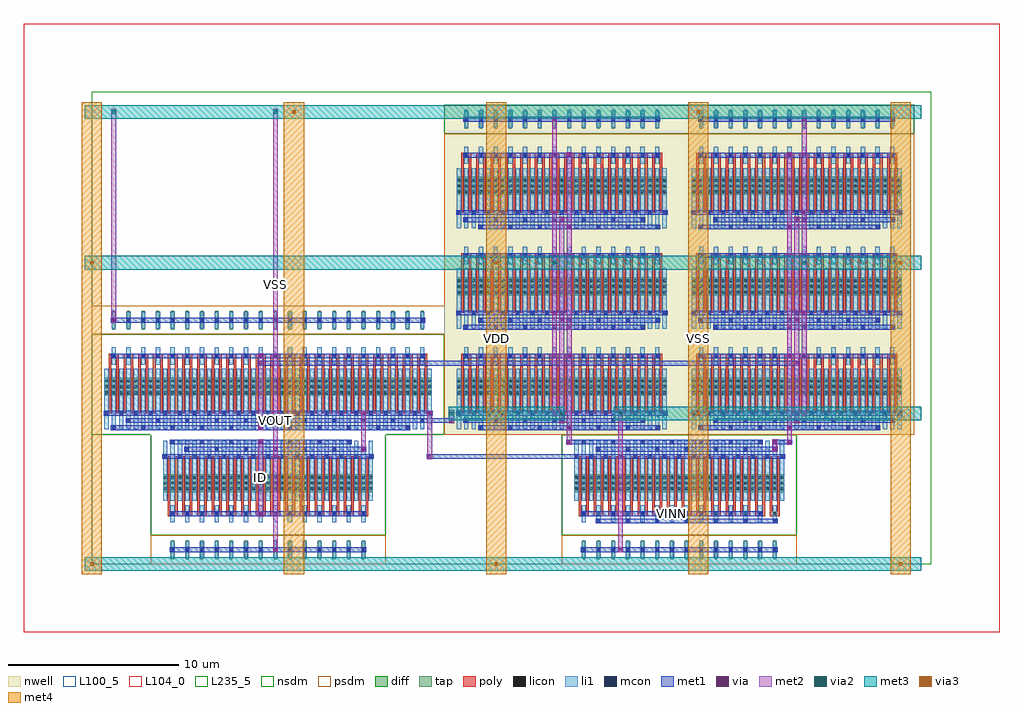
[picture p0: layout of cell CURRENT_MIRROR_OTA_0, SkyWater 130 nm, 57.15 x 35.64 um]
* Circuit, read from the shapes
.subckt CURRENT_MIRROR_OTA_0 ID VDD VINN VINP VOUT VSS
XM1 n1 n1 n2 VSS sky130_fd_pr__nfet_01v8 w=1.05 l=0.15 m=22
XM2 VOUT n1 n2 VSS sky130_fd_pr__nfet_01v8 w=1.05 l=0.15 m=22
XM3 ID ID VSS VSS sky130_fd_pr__nfet_01v8 w=1.05 l=0.15 m=14
XM4 n2 ID VSS VSS sky130_fd_pr__nfet_01v8 w=1.05 l=0.15 m=14
XM5 n3 VINN n2 VSS sky130_fd_pr__nfet_01v8 w=1.05 l=0.15 m=14
XM6 n4 VINP n2 VSS sky130_fd_pr__nfet_01v8 w=1.05 l=0.15 m=14
XM7 VOUT n3 VDD VDD sky130_fd_pr__pfet_01v8 w=1.05 l=0.15 m=42
XM8 n3 n3 VDD VDD sky130_fd_pr__pfet_01v8 w=1.05 l=0.15 m=42
XM9 n4 n4 VDD VDD sky130_fd_pr__pfet_01v8 w=1.05 l=0.15 m=42
XM10 n1 n4 VDD VDD sky130_fd_pr__pfet_01v8 w=1.05 l=0.15 m=42
.ends

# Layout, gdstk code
from math import pi, radians
import gdstk
lib = gdstk.Library(unit=1e-6, precision=1e-09)
def R(c, l, rs):  # rectangles x0, y0, x1, y1
    for r in rs: c.add(gdstk.rectangle(r[:2], r[2:], *l))
def A(c, l, x, y, w, h, nx, ny, dx, dy):  # array of equal rectangles
    R(c, l, [(x+i*dx, y+j*dy, x+i*dx+w, y+j*dy+h) for i in range(nx) for j in range(ny)])
def P(c, l, *ps):  # polygons
    for p in ps: c.add(gdstk.Polygon(p, *l))
nwell = (64, 20)
diff = (65, 20)
tap = (65, 44)
poly = (66, 20)
licon = (66, 44)
li1 = (67, 20)
mcon = (67, 44)
met1 = (68, 20)
via = (68, 44)
met2 = (69, 20)
via2 = (69, 44)
met3 = (70, 20)
via3 = (70, 44)
met4 = (71, 20)
nsdm = (93, 44)
psdm = (94, 20)
L100_5 = (100, 5)
L104_0 = (104, 0)
L235_5 = (235, 5)

scm_nmos_76211906_x7_y1_ = lib.new_cell('SCM_NMOS_76211906_X7_Y1_1725195708')
R(scm_nmos_76211906_x7_y1_, diff, [(0.735,2.31,13.025,3.36)])
A(scm_nmos_76211906_x7_y1_, tap, 1.205, 6.16, 0.17, 1.12, 14, 1, 0.86, 0)
A(scm_nmos_76211906_x7_y1_, poly, 1, 1.26, 0.15, 3.36, 28, 1, 0.43, 0)
A(scm_nmos_76211906_x7_y1_, poly, 1, 4.485, 0.58, 0.27, 14, 1, 0.86, 0)
A(scm_nmos_76211906_x7_y1_, licon, 0.775, 2.39, 0.17, 0.17, 3, 3, 0.43, 0.34)
A(scm_nmos_76211906_x7_y1_, licon, 1.635, 2.39, 0.17, 0.17, 3, 3, 0.43, 0.34)
A(scm_nmos_76211906_x7_y1_, licon, 2.495, 2.39, 0.17, 0.17, 3, 3, 0.43, 0.34)
A(scm_nmos_76211906_x7_y1_, licon, 3.355, 2.39, 0.17, 0.17, 3, 3, 0.43, 0.34)
A(scm_nmos_76211906_x7_y1_, licon, 4.215, 2.39, 0.17, 0.17, 3, 3, 0.43, 0.34)
A(scm_nmos_76211906_x7_y1_, licon, 5.075, 2.39, 0.17, 0.17, 3, 3, 0.43, 0.34)
A(scm_nmos_76211906_x7_y1_, licon, 5.935, 2.39, 0.17, 0.17, 3, 3, 0.43, 0.34)
A(scm_nmos_76211906_x7_y1_, licon, 6.795, 2.39, 0.17, 0.17, 3, 3, 0.43, 0.34)
A(scm_nmos_76211906_x7_y1_, licon, 7.655, 2.39, 0.17, 0.17, 3, 3, 0.43, 0.34)
A(scm_nmos_76211906_x7_y1_, licon, 8.515, 2.39, 0.17, 0.17, 3, 3, 0.43, 0.34)
A(scm_nmos_76211906_x7_y1_, licon, 9.375, 2.39, 0.17, 0.17, 3, 3, 0.43, 0.34)
A(scm_nmos_76211906_x7_y1_, licon, 10.235, 2.39, 0.17, 0.17, 3, 3, 0.43, 0.34)
A(scm_nmos_76211906_x7_y1_, licon, 11.095, 2.39, 0.17, 0.17, 3, 3, 0.43, 0.34)
A(scm_nmos_76211906_x7_y1_, licon, 11.955, 2.39, 0.17, 0.17, 3, 3, 0.43, 0.34)
A(scm_nmos_76211906_x7_y1_, licon, 1.205, 4.535, 0.17, 0.17, 14, 2, 0.86, 2.1)
A(scm_nmos_76211906_x7_y1_, li1, 0.735, 0.335, 0.25, 3.53, 29, 1, 0.43, 0)
A(scm_nmos_76211906_x7_y1_, li1, 1.165, 4.115, 0.25, 1.01, 14, 2, 0.86, 2.1)
A(scm_nmos_76211906_x7_y1_, mcon, 1.205, 0.335, 0.17, 0.17, 7, 1, 1.72, 0)
A(scm_nmos_76211906_x7_y1_, mcon, 2.065, 0.755, 0.17, 0.17, 7, 1, 1.72, 0)
A(scm_nmos_76211906_x7_y1_, mcon, 0.775, 1.175, 0.17, 0.17, 15, 1, 0.86, 0)
A(scm_nmos_76211906_x7_y1_, mcon, 1.205, 4.535, 0.17, 0.17, 14, 2, 0.86, 2.1)
R(scm_nmos_76211906_x7_y1_, met1, [(1.12,0.28,11.78,0.56), (1.98,0.7,12.64,0.98), (0.69,1.12,13.07,1.4), (1.12,4.48,12.64,4.76), (1.12,6.58,12.64,6.86)])
R(scm_nmos_76211906_x7_y1_, via, [(6.375,0.345,6.525,0.495), (7.235,1.185,7.385,1.335), (6.375,4.545,6.525,4.695), (7.235,6.645,7.385,6.795)])
R(scm_nmos_76211906_x7_y1_, met2, [(6.31,0.26,6.59,4.78), (7.17,1.1,7.45,6.88)])
R(scm_nmos_76211906_x7_y1_, nsdm, [(0,0,13.76,5.88)])
R(scm_nmos_76211906_x7_y1_, psdm, [(0,5.88,13.76,7.56)])
R(scm_nmos_76211906_x7_y1_, L100_5, [(0,0,13.76,7.56)])

scm_pmos_77874900_x7_y3_ = lib.new_cell('SCM_PMOS_77874900_X7_Y3_1725195710')
R(scm_pmos_77874900_x7_y3_, nwell, [(0,0,13.76,19.32)])
A(scm_pmos_77874900_x7_y3_, diff, 0.735, 2.31, 12.29, 1.05, 1, 3, 0, 5.88)
A(scm_pmos_77874900_x7_y3_, tap, 1.205, 17.92, 0.17, 1.12, 14, 1, 0.86, 0)
A(scm_pmos_77874900_x7_y3_, poly, 1, 1.26, 0.15, 3.36, 28, 3, 0.43, 5.88)
A(scm_pmos_77874900_x7_y3_, poly, 1, 4.485, 0.58, 0.27, 14, 3, 0.86, 5.88)
A(scm_pmos_77874900_x7_y3_, licon, 0.775, 2.39, 0.17, 0.17, 3, 3, 0.43, 0.34)
A(scm_pmos_77874900_x7_y3_, licon, 1.635, 2.39, 0.17, 0.17, 3, 3, 0.43, 0.34)
A(scm_pmos_77874900_x7_y3_, licon, 2.495, 2.39, 0.17, 0.17, 3, 3, 0.43, 0.34)
A(scm_pmos_77874900_x7_y3_, licon, 3.355, 2.39, 0.17, 0.17, 3, 3, 0.43, 0.34)
A(scm_pmos_77874900_x7_y3_, licon, 4.215, 2.39, 0.17, 0.17, 3, 3, 0.43, 0.34)
A(scm_pmos_77874900_x7_y3_, licon, 5.075, 2.39, 0.17, 0.17, 3, 3, 0.43, 0.34)
A(scm_pmos_77874900_x7_y3_, licon, 5.935, 2.39, 0.17, 0.17, 3, 3, 0.43, 0.34)
A(scm_pmos_77874900_x7_y3_, licon, 6.795, 2.39, 0.17, 0.17, 3, 3, 0.43, 0.34)
A(scm_pmos_77874900_x7_y3_, licon, 7.655, 2.39, 0.17, 0.17, 3, 3, 0.43, 0.34)
A(scm_pmos_77874900_x7_y3_, licon, 8.515, 2.39, 0.17, 0.17, 3, 3, 0.43, 0.34)
A(scm_pmos_77874900_x7_y3_, licon, 9.375, 2.39, 0.17, 0.17, 3, 3, 0.43, 0.34)
A(scm_pmos_77874900_x7_y3_, licon, 10.235, 2.39, 0.17, 0.17, 3, 3, 0.43, 0.34)
A(scm_pmos_77874900_x7_y3_, licon, 11.095, 2.39, 0.17, 0.17, 3, 3, 0.43, 0.34)
A(scm_pmos_77874900_x7_y3_, licon, 11.955, 2.39, 0.17, 0.17, 3, 3, 0.43, 0.34)
A(scm_pmos_77874900_x7_y3_, licon, 1.205, 4.535, 0.17, 0.17, 14, 3, 0.86, 5.88)
A(scm_pmos_77874900_x7_y3_, licon, 0.775, 8.27, 0.17, 0.17, 3, 3, 0.43, 0.34)
A(scm_pmos_77874900_x7_y3_, licon, 1.635, 8.27, 0.17, 0.17, 3, 3, 0.43, 0.34)
A(scm_pmos_77874900_x7_y3_, licon, 2.495, 8.27, 0.17, 0.17, 3, 3, 0.43, 0.34)
A(scm_pmos_77874900_x7_y3_, licon, 3.355, 8.27, 0.17, 0.17, 3, 3, 0.43, 0.34)
A(scm_pmos_77874900_x7_y3_, licon, 4.215, 8.27, 0.17, 0.17, 3, 3, 0.43, 0.34)
A(scm_pmos_77874900_x7_y3_, licon, 5.075, 8.27, 0.17, 0.17, 3, 3, 0.43, 0.34)
A(scm_pmos_77874900_x7_y3_, licon, 5.935, 8.27, 0.17, 0.17, 3, 3, 0.43, 0.34)
A(scm_pmos_77874900_x7_y3_, licon, 6.795, 8.27, 0.17, 0.17, 3, 3, 0.43, 0.34)
A(scm_pmos_77874900_x7_y3_, licon, 7.655, 8.27, 0.17, 0.17, 3, 3, 0.43, 0.34)
A(scm_pmos_77874900_x7_y3_, licon, 8.515, 8.27, 0.17, 0.17, 3, 3, 0.43, 0.34)
A(scm_pmos_77874900_x7_y3_, licon, 9.375, 8.27, 0.17, 0.17, 3, 3, 0.43, 0.34)
A(scm_pmos_77874900_x7_y3_, licon, 10.235, 8.27, 0.17, 0.17, 3, 3, 0.43, 0.34)
A(scm_pmos_77874900_x7_y3_, licon, 11.095, 8.27, 0.17, 0.17, 3, 3, 0.43, 0.34)
A(scm_pmos_77874900_x7_y3_, licon, 11.955, 8.27, 0.17, 0.17, 3, 3, 0.43, 0.34)
A(scm_pmos_77874900_x7_y3_, licon, 0.775, 14.15, 0.17, 0.17, 3, 3, 0.43, 0.34)
A(scm_pmos_77874900_x7_y3_, licon, 1.635, 14.15, 0.17, 0.17, 3, 3, 0.43, 0.34)
A(scm_pmos_77874900_x7_y3_, licon, 2.495, 14.15, 0.17, 0.17, 3, 3, 0.43, 0.34)
A(scm_pmos_77874900_x7_y3_, licon, 3.355, 14.15, 0.17, 0.17, 3, 3, 0.43, 0.34)
A(scm_pmos_77874900_x7_y3_, licon, 4.215, 14.15, 0.17, 0.17, 3, 3, 0.43, 0.34)
A(scm_pmos_77874900_x7_y3_, licon, 5.075, 14.15, 0.17, 0.17, 3, 3, 0.43, 0.34)
A(scm_pmos_77874900_x7_y3_, licon, 5.935, 14.15, 0.17, 0.17, 3, 3, 0.43, 0.34)
A(scm_pmos_77874900_x7_y3_, licon, 6.795, 14.15, 0.17, 0.17, 3, 3, 0.43, 0.34)
A(scm_pmos_77874900_x7_y3_, licon, 7.655, 14.15, 0.17, 0.17, 3, 3, 0.43, 0.34)
A(scm_pmos_77874900_x7_y3_, licon, 8.515, 14.15, 0.17, 0.17, 3, 3, 0.43, 0.34)
A(scm_pmos_77874900_x7_y3_, licon, 9.375, 14.15, 0.17, 0.17, 3, 3, 0.43, 0.34)
A(scm_pmos_77874900_x7_y3_, licon, 10.235, 14.15, 0.17, 0.17, 3, 3, 0.43, 0.34)
A(scm_pmos_77874900_x7_y3_, licon, 11.095, 14.15, 0.17, 0.17, 3, 3, 0.43, 0.34)
A(scm_pmos_77874900_x7_y3_, licon, 11.955, 14.15, 0.17, 0.17, 3, 3, 0.43, 0.34)
R(scm_pmos_77874900_x7_y3_, licon, [(1.205,18.395,1.375,18.565), (1.205,18.395,1.375,18.565), (1.205,18.395,1.375,18.565), (2.065,18.395,2.235,18.565), (2.065,18.395,2.235,18.565), (2.065,18.395,2.235,18.565), (2.925,18.395,3.095,18.565), (2.925,18.395,3.095,18.565), (2.925,18.395,3.095,18.565), (3.785,18.395,3.955,18.565), (3.785,18.395,3.955,18.565), (3.785,18.395,3.955,18.565), (4.645,18.395,4.815,18.565), (4.645,18.395,4.815,18.565), (4.645,18.395,4.815,18.565), (5.505,18.395,5.675,18.565), (5.505,18.395,5.675,18.565), (5.505,18.395,5.675,18.565), (6.365,18.395,6.535,18.565), (6.365,18.395,6.535,18.565), (6.365,18.395,6.535,18.565), (7.225,18.395,7.395,18.565), (7.225,18.395,7.395,18.565), (7.225,18.395,7.395,18.565), (8.085,18.395,8.255,18.565), (8.085,18.395,8.255,18.565), (8.085,18.395,8.255,18.565), (8.945,18.395,9.115,18.565), (8.945,18.395,9.115,18.565), (8.945,18.395,9.115,18.565), (9.805,18.395,9.975,18.565), (9.805,18.395,9.975,18.565), (9.805,18.395,9.975,18.565), (10.665,18.395,10.835,18.565), (10.665,18.395,10.835,18.565), (10.665,18.395,10.835,18.565), (11.525,18.395,11.695,18.565), (11.525,18.395,11.695,18.565), (11.525,18.395,11.695,18.565), (12.385,18.395,12.555,18.565), (12.385,18.395,12.555,18.565), (12.385,18.395,12.555,18.565)])
A(scm_pmos_77874900_x7_y3_, li1, 0.735, 0.335, 0.25, 3.53, 29, 3, 0.43, 5.88)
A(scm_pmos_77874900_x7_y3_, li1, 1.165, 4.115, 0.25, 1.01, 14, 3, 0.86, 5.88)
A(scm_pmos_77874900_x7_y3_, li1, 1.165, 17.975, 0.25, 1.01, 14, 1, 0.86, 0)
A(scm_pmos_77874900_x7_y3_, mcon, 1.205, 0.335, 0.17, 0.17, 7, 2, 1.72, 6.3)
A(scm_pmos_77874900_x7_y3_, mcon, 2.065, 0.755, 0.17, 0.17, 7, 2, 1.72, 5.46)
A(scm_pmos_77874900_x7_y3_, mcon, 0.775, 1.175, 0.17, 0.17, 15, 3, 0.86, 5.88)
A(scm_pmos_77874900_x7_y3_, mcon, 1.205, 4.535, 0.17, 0.17, 14, 3, 0.86, 5.88)
A(scm_pmos_77874900_x7_y3_, mcon, 1.205, 12.095, 0.17, 0.17, 7, 1, 1.72, 0)
A(scm_pmos_77874900_x7_y3_, mcon, 2.065, 12.515, 0.17, 0.17, 7, 1, 1.72, 0)
A(scm_pmos_77874900_x7_y3_, mcon, 1.205, 18.395, 0.17, 0.17, 14, 1, 0.86, 0)
A(scm_pmos_77874900_x7_y3_, met1, 0.69, 1.12, 12.38, 0.28, 1, 3, 0, 5.88)
A(scm_pmos_77874900_x7_y3_, met1, 1.12, 4.48, 11.52, 0.28, 1, 3, 0, 5.88)
R(scm_pmos_77874900_x7_y3_, met1, [(1.12,0.28,11.78,0.56), (1.98,0.7,12.64,0.98), (1.98,6.16,12.64,6.44), (1.12,6.58,11.78,6.86), (1.12,12.04,11.78,12.32), (1.98,12.46,12.64,12.74), (1.12,18.34,12.64,18.62)])
A(scm_pmos_77874900_x7_y3_, via, 6.805, 0.765, 0.15, 0.15, 1, 3, 0, 5.88)
A(scm_pmos_77874900_x7_y3_, via, 7.235, 1.185, 0.15, 0.15, 1, 3, 0, 5.88)
R(scm_pmos_77874900_x7_y3_, via, [(6.375,0.345,6.525,0.495), (6.375,4.545,6.525,4.695), (6.375,6.225,6.525,6.375), (6.375,10.425,6.525,10.575), (6.375,12.105,6.525,12.255), (6.375,16.305,6.525,16.455), (7.235,18.405,7.385,18.555)])
R(scm_pmos_77874900_x7_y3_, met2, [(6.31,0.26,6.59,16.54), (6.74,0.68,7.02,12.76), (7.17,1.1,7.45,18.64)])
R(scm_pmos_77874900_x7_y3_, nsdm, [(0,17.64,13.76,19.32)])
R(scm_pmos_77874900_x7_y3_, psdm, [(0,0,13.76,17.64)])
R(scm_pmos_77874900_x7_y3_, L100_5, [(0,0,13.76,19.32)])

scm_nmos_b_90984876_x11_ = lib.new_cell('SCM_NMOS_B_90984876_X11_Y1_1725195709')
R(scm_nmos_b_90984876_x11_, diff, [(0.735,2.31,19.905,3.36)])
A(scm_nmos_b_90984876_x11_, tap, 1.205, 6.16, 0.17, 1.12, 22, 1, 0.86, 0)
A(scm_nmos_b_90984876_x11_, poly, 1, 1.26, 0.15, 3.36, 44, 1, 0.43, 0)
A(scm_nmos_b_90984876_x11_, poly, 1, 4.485, 0.58, 0.27, 22, 1, 0.86, 0)
A(scm_nmos_b_90984876_x11_, licon, 0.775, 2.39, 0.17, 0.17, 3, 3, 0.43, 0.34)
A(scm_nmos_b_90984876_x11_, licon, 1.635, 2.39, 0.17, 0.17, 3, 3, 0.43, 0.34)
A(scm_nmos_b_90984876_x11_, licon, 2.495, 2.39, 0.17, 0.17, 3, 3, 0.43, 0.34)
A(scm_nmos_b_90984876_x11_, licon, 3.355, 2.39, 0.17, 0.17, 3, 3, 0.43, 0.34)
A(scm_nmos_b_90984876_x11_, licon, 4.215, 2.39, 0.17, 0.17, 3, 3, 0.43, 0.34)
A(scm_nmos_b_90984876_x11_, licon, 5.075, 2.39, 0.17, 0.17, 3, 3, 0.43, 0.34)
A(scm_nmos_b_90984876_x11_, licon, 5.935, 2.39, 0.17, 0.17, 3, 3, 0.43, 0.34)
A(scm_nmos_b_90984876_x11_, licon, 6.795, 2.39, 0.17, 0.17, 3, 3, 0.43, 0.34)
A(scm_nmos_b_90984876_x11_, licon, 7.655, 2.39, 0.17, 0.17, 3, 3, 0.43, 0.34)
A(scm_nmos_b_90984876_x11_, licon, 8.515, 2.39, 0.17, 0.17, 3, 3, 0.43, 0.34)
A(scm_nmos_b_90984876_x11_, licon, 9.375, 2.39, 0.17, 0.17, 3, 3, 0.43, 0.34)
A(scm_nmos_b_90984876_x11_, licon, 10.235, 2.39, 0.17, 0.17, 3, 3, 0.43, 0.34)
A(scm_nmos_b_90984876_x11_, licon, 11.095, 2.39, 0.17, 0.17, 3, 3, 0.43, 0.34)
A(scm_nmos_b_90984876_x11_, licon, 11.955, 2.39, 0.17, 0.17, 3, 3, 0.43, 0.34)
A(scm_nmos_b_90984876_x11_, licon, 12.815, 2.39, 0.17, 0.17, 3, 3, 0.43, 0.34)
A(scm_nmos_b_90984876_x11_, licon, 13.675, 2.39, 0.17, 0.17, 3, 3, 0.43, 0.34)
A(scm_nmos_b_90984876_x11_, licon, 14.535, 2.39, 0.17, 0.17, 3, 3, 0.43, 0.34)
A(scm_nmos_b_90984876_x11_, licon, 15.395, 2.39, 0.17, 0.17, 3, 3, 0.43, 0.34)
A(scm_nmos_b_90984876_x11_, licon, 16.255, 2.39, 0.17, 0.17, 3, 3, 0.43, 0.34)
A(scm_nmos_b_90984876_x11_, licon, 17.115, 2.39, 0.17, 0.17, 3, 3, 0.43, 0.34)
A(scm_nmos_b_90984876_x11_, licon, 17.975, 2.39, 0.17, 0.17, 3, 3, 0.43, 0.34)
A(scm_nmos_b_90984876_x11_, licon, 18.835, 2.39, 0.17, 0.17, 3, 3, 0.43, 0.34)
A(scm_nmos_b_90984876_x11_, licon, 1.205, 4.535, 0.17, 0.17, 22, 2, 0.86, 2.1)
A(scm_nmos_b_90984876_x11_, li1, 0.735, 0.335, 0.25, 3.53, 45, 1, 0.43, 0)
A(scm_nmos_b_90984876_x11_, li1, 1.165, 4.115, 0.25, 1.01, 22, 2, 0.86, 2.1)
A(scm_nmos_b_90984876_x11_, mcon, 1.205, 0.335, 0.17, 0.17, 11, 1, 1.72, 0)
A(scm_nmos_b_90984876_x11_, mcon, 2.065, 0.755, 0.17, 0.17, 11, 1, 1.72, 0)
A(scm_nmos_b_90984876_x11_, mcon, 0.775, 1.175, 0.17, 0.17, 23, 1, 0.86, 0)
A(scm_nmos_b_90984876_x11_, mcon, 1.205, 4.535, 0.17, 0.17, 22, 2, 0.86, 2.1)
R(scm_nmos_b_90984876_x11_, met1, [(1.12,0.28,18.66,0.56), (1.98,0.7,19.52,0.98), (0.69,1.12,19.95,1.4), (1.12,4.48,19.52,4.76), (1.12,6.58,19.52,6.86)])
R(scm_nmos_b_90984876_x11_, via, [(9.815,0.345,9.965,0.495), (9.815,4.545,9.965,4.695)])
R(scm_nmos_b_90984876_x11_, met2, [(9.75,0.26,10.03,4.78)])
R(scm_nmos_b_90984876_x11_, nsdm, [(0,0,20.64,5.88)])
R(scm_nmos_b_90984876_x11_, psdm, [(0,5.88,20.64,7.56)])
R(scm_nmos_b_90984876_x11_, L100_5, [(0,0,20.64,7.56)])

dp_nmos_b_14578568_x7_y1 = lib.new_cell('DP_NMOS_B_14578568_X7_Y1_1725195707')
R(dp_nmos_b_14578568_x7_y1, diff, [(0.735,2.31,13.025,3.36)])
A(dp_nmos_b_14578568_x7_y1, tap, 1.205, 6.16, 0.17, 1.12, 14, 1, 0.86, 0)
A(dp_nmos_b_14578568_x7_y1, poly, 1, 1.26, 0.15, 3.36, 28, 1, 0.43, 0)
A(dp_nmos_b_14578568_x7_y1, poly, 1, 4.485, 0.58, 0.27, 14, 1, 0.86, 0)
A(dp_nmos_b_14578568_x7_y1, licon, 0.775, 2.39, 0.17, 0.17, 3, 3, 0.43, 0.34)
A(dp_nmos_b_14578568_x7_y1, licon, 1.635, 2.39, 0.17, 0.17, 3, 3, 0.43, 0.34)
A(dp_nmos_b_14578568_x7_y1, licon, 2.495, 2.39, 0.17, 0.17, 3, 3, 0.43, 0.34)
A(dp_nmos_b_14578568_x7_y1, licon, 3.355, 2.39, 0.17, 0.17, 3, 3, 0.43, 0.34)
A(dp_nmos_b_14578568_x7_y1, licon, 4.215, 2.39, 0.17, 0.17, 3, 3, 0.43, 0.34)
A(dp_nmos_b_14578568_x7_y1, licon, 5.075, 2.39, 0.17, 0.17, 3, 3, 0.43, 0.34)
A(dp_nmos_b_14578568_x7_y1, licon, 5.935, 2.39, 0.17, 0.17, 3, 3, 0.43, 0.34)
A(dp_nmos_b_14578568_x7_y1, licon, 6.795, 2.39, 0.17, 0.17, 3, 3, 0.43, 0.34)
A(dp_nmos_b_14578568_x7_y1, licon, 7.655, 2.39, 0.17, 0.17, 3, 3, 0.43, 0.34)
A(dp_nmos_b_14578568_x7_y1, licon, 8.515, 2.39, 0.17, 0.17, 3, 3, 0.43, 0.34)
A(dp_nmos_b_14578568_x7_y1, licon, 9.375, 2.39, 0.17, 0.17, 3, 3, 0.43, 0.34)
A(dp_nmos_b_14578568_x7_y1, licon, 10.235, 2.39, 0.17, 0.17, 3, 3, 0.43, 0.34)
A(dp_nmos_b_14578568_x7_y1, licon, 11.095, 2.39, 0.17, 0.17, 3, 3, 0.43, 0.34)
A(dp_nmos_b_14578568_x7_y1, licon, 11.955, 2.39, 0.17, 0.17, 3, 3, 0.43, 0.34)
A(dp_nmos_b_14578568_x7_y1, licon, 1.205, 4.535, 0.17, 0.17, 14, 2, 0.86, 2.1)
A(dp_nmos_b_14578568_x7_y1, li1, 0.735, 0.335, 0.25, 3.53, 29, 1, 0.43, 0)
A(dp_nmos_b_14578568_x7_y1, li1, 1.165, 4.115, 0.25, 1.01, 14, 2, 0.86, 2.1)
A(dp_nmos_b_14578568_x7_y1, mcon, 1.205, 0.335, 0.17, 0.17, 7, 2, 1.72, 4.2)
A(dp_nmos_b_14578568_x7_y1, mcon, 2.065, 0.755, 0.17, 0.17, 7, 2, 1.72, 4.2)
A(dp_nmos_b_14578568_x7_y1, mcon, 0.775, 1.175, 0.17, 0.17, 15, 1, 0.86, 0)
A(dp_nmos_b_14578568_x7_y1, mcon, 1.205, 6.635, 0.17, 0.17, 14, 1, 0.86, 0)
R(dp_nmos_b_14578568_x7_y1, met1, [(1.12,0.28,11.78,0.56), (1.98,0.7,12.64,0.98), (0.69,1.12,13.07,1.4), (1.12,4.48,11.78,4.76), (1.98,4.9,12.64,5.18), (1.12,6.58,12.64,6.86)])
R(dp_nmos_b_14578568_x7_y1, nsdm, [(0,0,13.76,5.88)])
R(dp_nmos_b_14578568_x7_y1, psdm, [(0,5.88,13.76,7.56)])
R(dp_nmos_b_14578568_x7_y1, L100_5, [(0,0,13.76,7.56)])

current_mirror_ota_0 = lib.new_cell('CURRENT_MIRROR_OTA_0')
R(current_mirror_ota_0, met1, [(30.8,0.7,31.12,0.98), (30.8,0.7,31.12,0.98), (19.62,6.16,19.94,6.44), (19.62,6.16,19.94,6.44), (19.78,6.16,28.38,6.44), (15.75,6.58,16.07,6.86), (15.75,6.58,16.07,6.86), (15.75,6.58,16.07,6.86), (15.75,6.58,16.07,6.86), (39.83,6.58,40.15,6.86), (39.83,6.58,40.15,6.86), (27.79,7,28.11,7.28), (27.79,7,28.11,7.28), (27.95,7,28.81,7.28), (39.83,7,40.15,7.28), (39.83,7,40.15,7.28), (39.99,7,40.85,7.28), (40.69,7,41.01,7.28), (40.69,7,41.01,7.28), (19.35,8.26,21.07,8.54), (20.91,8.26,21.23,8.54), (20.91,8.26,21.23,8.54), (15.75,8.68,16.07,8.96), (15.75,8.68,16.07,8.96), (15.75,8.68,16.07,8.96), (15.75,8.68,16.07,8.96), (19.62,8.68,19.94,8.96), (19.62,8.68,19.94,8.96), (9.73,11.62,10.05,11.9), (9.73,11.62,10.05,11.9), (9.89,11.62,41.28,11.9), (41.12,11.62,41.44,11.9), (41.12,11.62,41.44,11.9), (1.13,14.14,1.45,14.42), (1.13,14.14,1.45,14.42), (1.13,14.14,1.45,14.42)])
P(current_mirror_ota_0, met1, [(0,0),(0,0),(0,0),(0,0)],
  [(0,0),(0,0),(0,0),(0,0)],
  [(0,0),(0,0),(0,0),(0,0)],
  [(0,0),(0,0),(0,0),(0,0)],
  [(0,0),(0,0),(0,0),(0,0)],
  [(0,0),(0,0),(0,0),(0,0)],
  [(0,0),(0,0),(0,0),(0,0)],
  [(0,0),(0,0),(0,0),(0,0)],
  [(0,0),(0,0),(0,0),(0,0)],
  [(0,0),(0,0),(0,0),(0,0)],
  [(0,0),(0,0),(0,0),(0,0)],
  [(0,0),(0,0),(0,0),(0,0)],
  [(0,0),(0,0),(0,0),(0,0)])
R(current_mirror_ota_0, via, [(30.885,0.765,31.035,0.915), (30.885,0.765,31.035,0.915), (19.705,6.225,19.855,6.375), (19.705,6.225,19.855,6.375), (15.835,6.645,15.985,6.795), (15.835,6.645,15.985,6.795), (15.835,6.645,15.985,6.795), (15.835,6.645,15.985,6.795), (39.915,6.645,40.065,6.795), (39.915,6.645,40.065,6.795), (27.875,7.065,28.025,7.215), (27.875,7.065,28.025,7.215), (39.915,7.065,40.065,7.215), (39.915,7.065,40.065,7.215), (40.775,7.065,40.925,7.215), (40.775,7.065,40.925,7.215), (20.995,8.325,21.145,8.475), (20.995,8.325,21.145,8.475), (15.835,8.745,15.985,8.895), (15.835,8.745,15.985,8.895), (15.835,8.745,15.985,8.895), (15.835,8.745,15.985,8.895), (19.705,8.745,19.855,8.895), (19.705,8.745,19.855,8.895), (9.815,11.685,9.965,11.835), (9.815,11.685,9.965,11.835), (41.205,11.685,41.355,11.835), (41.205,11.685,41.355,11.835), (1.215,14.205,1.365,14.355), (1.215,14.205,1.365,14.355), (1.215,14.205,1.365,14.355)])
R(current_mirror_ota_0, met2, [(30.82,0.68,31.1,1), (30.82,0.68,31.1,1), (30.82,0.84,31.1,8.82), (19.64,6.14,19.92,6.46), (19.64,6.14,19.92,6.46), (10.61,6.3,10.89,26.46), (19.64,6.3,19.92,8.82), (15.77,6.56,16.05,6.88), (15.77,6.56,16.05,6.88), (15.77,6.56,16.05,6.88), (15.77,6.56,16.05,6.88), (39.85,6.56,40.13,6.88), (39.85,6.56,40.13,6.88), (15.77,6.72,16.05,8.82), (39.85,6.72,40.13,7.14), (27.81,6.98,28.09,7.3), (27.81,6.98,28.09,7.3), (39.85,6.98,40.13,7.3), (39.85,6.98,40.13,7.3), (40.71,6.98,40.99,7.3), (40.71,6.98,40.99,7.3), (27.81,7.14,28.09,7.98), (40.71,7.14,40.99,7.98), (20.93,8.24,21.21,8.56), (20.93,8.24,21.21,8.56), (20.93,8.4,21.21,8.82), (20.93,8.635,21.21,9.005), (20.93,8.635,21.21,9.005), (27.38,8.635,27.66,9.005), (27.38,8.635,27.66,9.005), (30.82,8.635,31.1,9.005), (30.82,8.635,31.1,9.005), (15.77,8.66,16.05,8.98), (15.77,8.66,16.05,8.98), (15.77,8.66,16.05,8.98), (15.77,8.66,16.05,8.98), (19.64,8.66,19.92,8.98), (19.64,8.66,19.92,8.98), (9.75,11.6,10.03,11.92), (9.75,11.6,10.03,11.92), (41.14,11.6,41.42,11.92), (41.14,11.6,41.42,11.92), (1.15,14.12,1.43,14.44), (1.15,14.12,1.43,14.44), (1.15,14.12,1.43,14.44), (1.15,14.28,1.43,26.46), (26.95,17.455,27.23,17.825), (26.95,17.455,27.23,17.825), (26.95,17.455,27.23,17.825), (41.57,17.455,41.85,17.825), (41.57,17.455,41.85,17.825), (1.15,26.275,1.43,26.645), (1.15,26.275,1.43,26.645), (1.15,26.275,1.43,26.645), (10.61,26.275,10.89,26.645), (10.61,26.275,10.89,26.645), (10.61,26.275,10.89,26.645), (10.61,26.275,10.89,26.645)])
P(current_mirror_ota_0, met2, [(0,0),(0,0),(0,0),(0,0)],
  [(0,0),(0,0),(0,0),(0,0)],
  [(0,0),(0,0),(0,0),(0,0)],
  [(0,0),(0,0),(0,0),(0,0)],
  [(0,0),(0,0),(0,0),(0,0)],
  [(0,0),(0,0),(0,0),(0,0)],
  [(0,0),(0,0),(0,0),(0,0)],
  [(0,0),(0,0),(0,0),(0,0)],
  [(0,0),(0,0),(0,0),(0,0)],
  [(0,0),(0,0),(0,0),(0,0)])
R(current_mirror_ota_0, via2, [(20.97,8.72,21.17,8.92), (20.97,8.72,21.17,8.92), (27.42,8.72,27.62,8.92), (27.42,8.72,27.62,8.92), (30.86,8.72,31.06,8.92), (30.86,8.72,31.06,8.92), (26.99,17.54,27.19,17.74), (26.99,17.54,27.19,17.74), (26.99,17.54,27.19,17.74), (41.61,17.54,41.81,17.74), (41.61,17.54,41.81,17.74), (1.19,26.36,1.39,26.56), (1.19,26.36,1.39,26.56), (1.19,26.36,1.39,26.56), (10.65,26.36,10.85,26.56), (10.65,26.36,10.85,26.56), (10.65,26.36,10.85,26.56), (10.65,26.36,10.85,26.56)])
A(current_mirror_ota_0, met3, -0.4, -0.4, 4.24, 0.8, 3, 2, 3.44, 17.64)
A(current_mirror_ota_0, met3, -0.165, -0.4, 0.33, 0.8, 3, 1, 23.68, 0)
A(current_mirror_ota_0, met3, 23.68, -0.4, 4.24, 0.8, 3, 2, 3.44, 17.64)
A(current_mirror_ota_0, met3, 34, -0.4, 1.92, 0.8, 1, 4, 0, 8.82)
A(current_mirror_ota_0, met3, 35.12, -0.4, 3.12, 0.8, 1, 4, 0, 8.82)
A(current_mirror_ota_0, met3, 37.44, -0.4, 4.24, 0.8, 1, 4, 0, 8.82)
A(current_mirror_ota_0, met3, 40.88, -0.4, 4.24, 0.8, 1, 4, 0, 8.82)
A(current_mirror_ota_0, met3, 44.32, -0.4, 3.44, 0.8, 1, 4, 0, 8.82)
A(current_mirror_ota_0, met3, 46.96, -0.4, 1.6, 0.8, 1, 4, 0, 8.82)
A(current_mirror_ota_0, met3, -0.4, 26.06, 4.24, 0.8, 3, 1, 3.44, 0)
A(current_mirror_ota_0, met3, 23.68, 26.06, 4.24, 0.8, 3, 1, 3.44, 0)
R(current_mirror_ota_0, met3, [(9.92,-0.4,12.24,0.4), (11.44,-0.4,14.16,0.4), (13.36,-0.4,17.6,0.4), (16.8,-0.4,21.04,0.4), (20.24,-0.4,24.08,0.4), (23.28,-0.4,24.48,0.4), (20.905,8.42,21.235,9.22), (20.905,8.42,21.235,9.22), (21.07,8.42,27.52,9.22), (27.355,8.42,27.685,9.22), (27.355,8.42,27.685,9.22), (30.56,8.42,34.8,9.22), (30.795,8.42,31.125,9.22), (30.795,8.42,31.125,9.22), (35.355,8.42,35.685,9.22), (-0.165,17.24,0.165,18.04), (9.92,17.24,12.24,18.04), (11.44,17.24,14.16,18.04), (13.36,17.24,17.6,18.04), (16.8,17.24,21.04,18.04), (20.24,17.24,24.08,18.04), (23.28,17.24,24.48,18.04), (23.515,17.24,23.845,18.04), (26.925,17.24,27.255,18.04), (26.925,17.24,27.255,18.04), (26.925,17.24,27.255,18.04), (41.545,17.24,41.875,18.04), (41.545,17.24,41.875,18.04), (47.195,17.24,47.525,18.04), (1.125,26.06,1.455,26.86), (1.125,26.06,1.455,26.86), (1.125,26.06,1.455,26.86), (9.92,26.06,12.24,26.86), (10.585,26.06,10.915,26.86), (10.585,26.06,10.915,26.86), (10.585,26.06,10.915,26.86), (10.585,26.06,10.915,26.86), (11.44,26.06,14.16,26.86), (11.675,26.06,12.005,26.86), (13.36,26.06,17.6,26.86), (16.8,26.06,21.04,26.86), (20.24,26.06,24.08,26.86), (23.28,26.06,24.48,26.86), (35.355,26.06,35.685,26.86)])
A(current_mirror_ota_0, via3, -0.1, -0.1, 0.2, 0.2, 3, 2, 23.68, 17.64)
R(current_mirror_ota_0, via3, [(35.42,8.72,35.62,8.92), (11.74,26.36,11.94,26.56), (35.42,26.36,35.62,26.56)])
A(current_mirror_ota_0, met4, -0.59, -0.59, 1.18, 10, 5, 3, 11.84, 8.82)
A(current_mirror_ota_0, met4, -0.59, -0.165, 1.18, 0.33, 3, 2, 23.68, 17.64)
R(current_mirror_ota_0, met4, [(34.93,8.655,36.11,8.985), (11.25,26.295,12.43,26.625), (34.93,26.295,36.11,26.625)])
R(current_mirror_ota_0, L104_0, [(-4,-4,53.15,31.64)])
R(current_mirror_ota_0, L235_5, [(0,0,49.15,27.64)])
current_mirror_ota_0.add(gdstk.Reference(scm_nmos_76211906_x7_y1_, (3.44,7.56), x_reflection=True))
current_mirror_ota_0.add(gdstk.Reference(scm_pmos_77874900_x7_y3_, (34.4,7.56), rotation=pi, x_reflection=True))
current_mirror_ota_0.add(gdstk.Reference(scm_pmos_77874900_x7_y3_, (34.4,7.56)))
current_mirror_ota_0.add(gdstk.Reference(scm_nmos_b_90984876_x11_, (0,7.56)))
current_mirror_ota_0.add(gdstk.Reference(dp_nmos_b_14578568_x7_y1, (27.52,7.56), x_reflection=True))
current_mirror_ota_0.add(gdstk.Label('ID', (9.89,5.04), layer=69, texttype=5))
current_mirror_ota_0.add(gdstk.Label('VOUT', (10.75,8.4), layer=68, texttype=5))
current_mirror_ota_0.add(gdstk.Label('VINN', (33.97,2.94), layer=68, texttype=5))
current_mirror_ota_0.add(gdstk.Label('VINP', (34.83,2.52), layer=68, texttype=5))
current_mirror_ota_0.add(gdstk.Label('VSS', (10.75,16.38), layer=69, texttype=5))
current_mirror_ota_0.add(gdstk.Label('VSS', (35.52,13.23), layer=71, texttype=5))
current_mirror_ota_0.add(gdstk.Label('VSS', (35.52,13.23), layer=71, texttype=5))
current_mirror_ota_0.add(gdstk.Label('VSS', (35.52,13.23), layer=71, texttype=5))
current_mirror_ota_0.add(gdstk.Label('VSS', (35.52,13.23), layer=71, texttype=5))
current_mirror_ota_0.add(gdstk.Label('VSS', (35.52,13.23), layer=71, texttype=5))
current_mirror_ota_0.add(gdstk.Label('VSS', (35.52,13.23), layer=71, texttype=5))
current_mirror_ota_0.add(gdstk.Label('VSS', (35.52,13.23), layer=71, texttype=5))
current_mirror_ota_0.add(gdstk.Label('VSS', (35.52,13.23), layer=71, texttype=5))
current_mirror_ota_0.add(gdstk.Label('VDD', (23.68,13.23), layer=71, texttype=5))
current_mirror_ota_0.add(gdstk.Label('VDD', (23.68,13.23), layer=71, texttype=5))
current_mirror_ota_0.add(gdstk.Label('VDD', (23.68,13.23), layer=71, texttype=5))
current_mirror_ota_0.add(gdstk.Label('VDD', (23.68,13.23), layer=71, texttype=5))

lib.write_gds('CURRENT_MIRROR_OTA_0.gds')
